One B-rep face of a CAD part: STEP entity #215.
In plain terms, the planar face has unit normal (1, 0, 0).
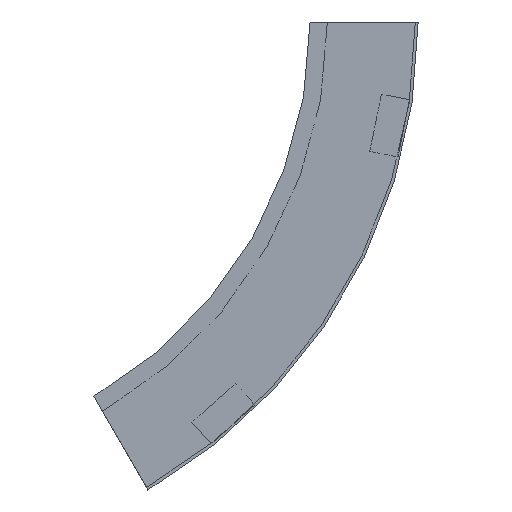
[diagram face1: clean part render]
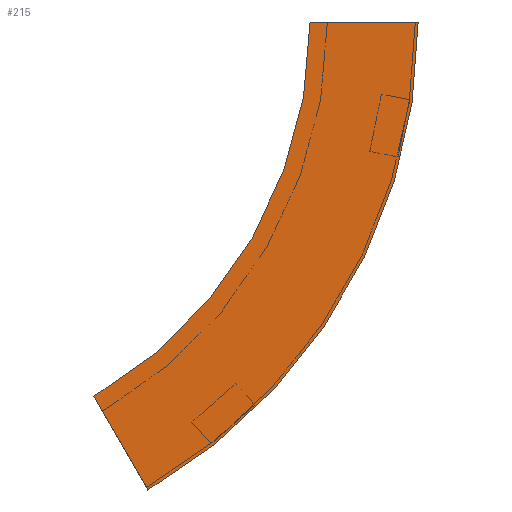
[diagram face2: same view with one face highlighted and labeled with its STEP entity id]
Its self-contained STEP definition (entity closure, numbers rounded to 3 decimals):
#23 = ORIENTED_EDGE ( 'NONE', *, *, #164, .T. ) ;
#26 = EDGE_CURVE ( 'NONE', #246, #280, #125, .T. ) ;
#30 = LINE ( 'NONE', #118, #296 ) ;
#75 = DIRECTION ( 'NONE',  ( 1., 0., 0. ) ) ;
#83 = CARTESIAN_POINT ( 'NONE',  ( 0., 150., -259.808 ) ) ;
#114 = PLANE ( 'NONE',  #219 ) ;
#118 = CARTESIAN_POINT ( 'NONE',  ( 0., 112.5, -324.76 ) ) ;
#119 = AXIS2_PLACEMENT_3D ( 'NONE', #554, #474, #410 ) ;
#121 = DIRECTION ( 'NONE',  ( 0., -1., 0. ) ) ;
#125 = CIRCLE ( 'NONE', #119, 375. ) ;
#160 = DIRECTION ( 'NONE',  ( 0., 0.5, 0.866 ) ) ;
#164 = EDGE_CURVE ( 'NONE', #280, #293, #30, .T. ) ;
#166 = CARTESIAN_POINT ( 'NONE',  ( 0., -75., 0. ) ) ;
#168 = EDGE_CURVE ( 'NONE', #372, #293, #392, .T. ) ;
#176 = DIRECTION ( 'NONE',  ( 0., 1., 0. ) ) ;
#191 = CARTESIAN_POINT ( 'NONE',  ( 0., 0., 0. ) ) ;
#211 = VECTOR ( 'NONE', #176, 1000. ) ;
#215 = ADVANCED_FACE ( 'NONE', ( #390 ), #114, .F. ) ;
#219 = AXIS2_PLACEMENT_3D ( 'NONE', #166, #432, #525 ) ;
#246 = VERTEX_POINT ( 'NONE', #568 ) ;
#265 = EDGE_CURVE ( 'NONE', #246, #372, #492, .T. ) ;
#280 = VERTEX_POINT ( 'NONE', #448 ) ;
#293 = VERTEX_POINT ( 'NONE', #83 ) ;
#296 = VECTOR ( 'NONE', #160, 1000. ) ;
#372 = VERTEX_POINT ( 'NONE', #191 ) ;
#380 = ORIENTED_EDGE ( 'NONE', *, *, #265, .F. ) ;
#390 = FACE_OUTER_BOUND ( 'NONE', #541, .T. ) ;
#391 = CARTESIAN_POINT ( 'NONE',  ( 0., 300., 0. ) ) ;
#392 = CIRCLE ( 'NONE', #533, 300. ) ;
#410 = DIRECTION ( 'NONE',  ( 0., -1., 0. ) ) ;
#432 = DIRECTION ( 'NONE',  ( -1., 0., 0. ) ) ;
#439 = CARTESIAN_POINT ( 'NONE',  ( 0., -75., 0. ) ) ;
#448 = CARTESIAN_POINT ( 'NONE',  ( 0., 112.5, -324.76 ) ) ;
#457 = ORIENTED_EDGE ( 'NONE', *, *, #26, .T. ) ;
#470 = ORIENTED_EDGE ( 'NONE', *, *, #168, .F. ) ;
#474 = DIRECTION ( 'NONE',  ( 1., 0., 0. ) ) ;
#492 = LINE ( 'NONE', #439, #211 ) ;
#525 = DIRECTION ( 'NONE',  ( 0., 0., 1. ) ) ;
#533 = AXIS2_PLACEMENT_3D ( 'NONE', #391, #75, #121 ) ;
#541 = EDGE_LOOP ( 'NONE', ( #470, #380, #457, #23 ) ) ;
#554 = CARTESIAN_POINT ( 'NONE',  ( 0., 300., 0. ) ) ;
#568 = CARTESIAN_POINT ( 'NONE',  ( 0., -75., 0. ) ) ;
